VERSION 5.7 ;
  NOWIREEXTENSIONATPIN ON ;
  DIVIDERCHAR "/" ;
  BUSBITCHARS "[]" ;
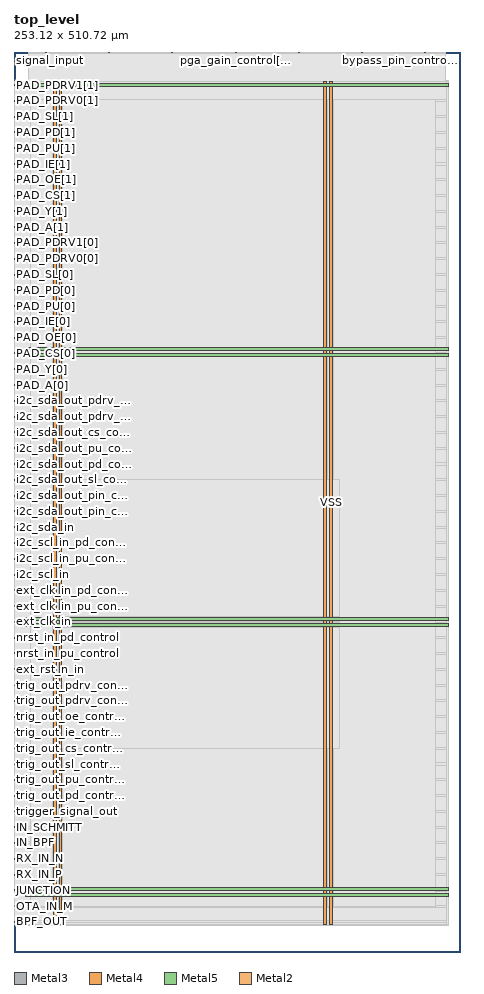
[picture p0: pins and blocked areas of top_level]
MACRO top_level
  CLASS BLOCK ;
  FOREIGN top_level ;
  ORIGIN 0.000 0.000 ;
  SIZE 253.120 BY 510.720 ;
  PIN BPF_OUT
    DIRECTION INPUT ;
    USE SIGNAL ;
    PORT
      LAYER Metal3 ;
        RECT 0.000 16.800 0.560 17.360 ;
    END
  END BPF_OUT
  PIN IN_BPF
    DIRECTION INPUT ;
    USE SIGNAL ;
    PORT
      LAYER Metal3 ;
        RECT 0.000 61.600 0.560 62.160 ;
    END
  END IN_BPF
  PIN IN_SCHMITT
    DIRECTION INPUT ;
    USE SIGNAL ;
    PORT
      LAYER Metal3 ;
        RECT 0.000 70.560 0.560 71.120 ;
    END
  END IN_SCHMITT
  PIN JUNCTION
    DIRECTION INPUT ;
    USE SIGNAL ;
    PORT
      LAYER Metal3 ;
        RECT 0.000 34.720 0.560 35.280 ;
    END
  END JUNCTION
  PIN OTA_IN_M
    DIRECTION INPUT ;
    USE SIGNAL ;
    PORT
      LAYER Metal3 ;
        RECT 0.000 25.760 0.560 26.320 ;
    END
  END OTA_IN_M
  PIN PAD_A[0]
    DIRECTION OUTPUT ;
    USE SIGNAL ;
    ANTENNADIFFAREA 0.897600 ;
    PORT
      LAYER Metal3 ;
        RECT 0.000 321.440 0.560 322.000 ;
    END
  END PAD_A[0]
  PIN PAD_A[1]
    DIRECTION OUTPUT ;
    USE SIGNAL ;
    ANTENNADIFFAREA 0.897600 ;
    PORT
      LAYER Metal3 ;
        RECT 0.000 411.040 0.560 411.600 ;
    END
  END PAD_A[1]
  PIN PAD_CS[0]
    DIRECTION OUTPUT ;
    USE SIGNAL ;
    ANTENNADIFFAREA 0.897600 ;
    PORT
      LAYER Metal3 ;
        RECT 0.000 339.360 0.560 339.920 ;
    END
  END PAD_CS[0]
  PIN PAD_CS[1]
    DIRECTION OUTPUT ;
    USE SIGNAL ;
    ANTENNADIFFAREA 0.897600 ;
    PORT
      LAYER Metal3 ;
        RECT 0.000 428.960 0.560 429.520 ;
    END
  END PAD_CS[1]
  PIN PAD_IE[0]
    DIRECTION OUTPUT ;
    USE SIGNAL ;
    ANTENNADIFFAREA 0.897600 ;
    PORT
      LAYER Metal3 ;
        RECT 0.000 357.280 0.560 357.840 ;
    END
  END PAD_IE[0]
  PIN PAD_IE[1]
    DIRECTION OUTPUT ;
    USE SIGNAL ;
    ANTENNADIFFAREA 0.897600 ;
    PORT
      LAYER Metal3 ;
        RECT 0.000 446.880 0.560 447.440 ;
    END
  END PAD_IE[1]
  PIN PAD_OE[0]
    DIRECTION OUTPUT ;
    USE SIGNAL ;
    ANTENNADIFFAREA 0.897600 ;
    PORT
      LAYER Metal3 ;
        RECT 0.000 348.320 0.560 348.880 ;
    END
  END PAD_OE[0]
  PIN PAD_OE[1]
    DIRECTION OUTPUT ;
    USE SIGNAL ;
    ANTENNADIFFAREA 0.897600 ;
    PORT
      LAYER Metal3 ;
        RECT 0.000 437.920 0.560 438.480 ;
    END
  END PAD_OE[1]
  PIN PAD_PDRV0[0]
    DIRECTION OUTPUT ;
    USE SIGNAL ;
    ANTENNADIFFAREA 0.536800 ;
    PORT
      LAYER Metal3 ;
        RECT 0.000 393.120 0.560 393.680 ;
    END
  END PAD_PDRV0[0]
  PIN PAD_PDRV0[1]
    DIRECTION OUTPUT ;
    USE SIGNAL ;
    ANTENNADIFFAREA 0.536800 ;
    PORT
      LAYER Metal3 ;
        RECT 0.000 482.720 0.560 483.280 ;
    END
  END PAD_PDRV0[1]
  PIN PAD_PDRV1[0]
    DIRECTION OUTPUT ;
    USE SIGNAL ;
    ANTENNADIFFAREA 0.536800 ;
    PORT
      LAYER Metal3 ;
        RECT 0.000 402.080 0.560 402.640 ;
    END
  END PAD_PDRV1[0]
  PIN PAD_PDRV1[1]
    DIRECTION OUTPUT ;
    USE SIGNAL ;
    ANTENNADIFFAREA 0.536800 ;
    PORT
      LAYER Metal3 ;
        RECT 0.000 491.680 0.560 492.240 ;
    END
  END PAD_PDRV1[1]
  PIN PAD_PD[0]
    DIRECTION OUTPUT ;
    USE SIGNAL ;
    ANTENNADIFFAREA 0.897600 ;
    PORT
      LAYER Metal3 ;
        RECT 0.000 375.200 0.560 375.760 ;
    END
  END PAD_PD[0]
  PIN PAD_PD[1]
    DIRECTION OUTPUT ;
    USE SIGNAL ;
    ANTENNADIFFAREA 0.897600 ;
    PORT
      LAYER Metal3 ;
        RECT 0.000 464.800 0.560 465.360 ;
    END
  END PAD_PD[1]
  PIN PAD_PU[0]
    DIRECTION OUTPUT ;
    USE SIGNAL ;
    ANTENNADIFFAREA 0.897600 ;
    PORT
      LAYER Metal3 ;
        RECT 0.000 366.240 0.560 366.800 ;
    END
  END PAD_PU[0]
  PIN PAD_PU[1]
    DIRECTION OUTPUT ;
    USE SIGNAL ;
    ANTENNADIFFAREA 0.897600 ;
    PORT
      LAYER Metal3 ;
        RECT 0.000 455.840 0.560 456.400 ;
    END
  END PAD_PU[1]
  PIN PAD_SL[0]
    DIRECTION OUTPUT ;
    USE SIGNAL ;
    ANTENNADIFFAREA 0.897600 ;
    PORT
      LAYER Metal3 ;
        RECT 0.000 384.160 0.560 384.720 ;
    END
  END PAD_SL[0]
  PIN PAD_SL[1]
    DIRECTION OUTPUT ;
    USE SIGNAL ;
    ANTENNADIFFAREA 0.897600 ;
    PORT
      LAYER Metal3 ;
        RECT 0.000 473.760 0.560 474.320 ;
    END
  END PAD_SL[1]
  PIN PAD_Y[0]
    DIRECTION INPUT ;
    USE SIGNAL ;
    ANTENNAGATEAREA 0.396000 ;
    PORT
      LAYER Metal3 ;
        RECT 0.000 330.400 0.560 330.960 ;
    END
  END PAD_Y[0]
  PIN PAD_Y[1]
    DIRECTION INPUT ;
    USE SIGNAL ;
    ANTENNAGATEAREA 0.396000 ;
    PORT
      LAYER Metal3 ;
        RECT 0.000 420.000 0.560 420.560 ;
    END
  END PAD_Y[1]
  PIN RX_IN_N
    DIRECTION INPUT ;
    USE SIGNAL ;
    PORT
      LAYER Metal3 ;
        RECT 0.000 52.640 0.560 53.200 ;
    END
  END RX_IN_N
  PIN RX_IN_P
    DIRECTION INPUT ;
    USE SIGNAL ;
    PORT
      LAYER Metal3 ;
        RECT 0.000 43.680 0.560 44.240 ;
    END
  END RX_IN_P
  PIN VDD
    DIRECTION INOUT ;
    USE POWER ;
    PORT
      LAYER Metal4 ;
        RECT 22.240 15.380 23.840 494.220 ;
    END
    PORT
      LAYER Metal4 ;
        RECT 175.840 15.380 177.440 494.220 ;
    END
    PORT
      LAYER Metal5 ;
        RECT 6.720 31.530 246.400 33.130 ;
    END
    PORT
      LAYER Metal5 ;
        RECT 6.720 184.710 246.400 186.310 ;
    END
    PORT
      LAYER Metal5 ;
        RECT 6.720 337.890 246.400 339.490 ;
    END
    PORT
      LAYER Metal5 ;
        RECT 6.720 491.070 246.400 492.670 ;
    END
  END VDD
  PIN VSS
    DIRECTION INOUT ;
    USE GROUND ;
    PORT
      LAYER Metal4 ;
        RECT 25.540 15.380 27.140 494.220 ;
    END
    PORT
      LAYER Metal4 ;
        RECT 179.140 15.380 180.740 494.220 ;
    END
    PORT
      LAYER Metal5 ;
        RECT 6.720 34.830 246.400 36.430 ;
    END
    PORT
      LAYER Metal5 ;
        RECT 6.720 188.010 246.400 189.610 ;
    END
    PORT
      LAYER Metal5 ;
        RECT 6.720 341.190 246.400 342.790 ;
    END
  END VSS
  PIN bypass_pin_control[0]
    DIRECTION OUTPUT ;
    USE SIGNAL ;
    ANTENNADIFFAREA 0.897600 ;
    PORT
      LAYER Metal2 ;
        RECT 232.960 510.160 233.520 510.720 ;
    END
  END bypass_pin_control[0]
  PIN bypass_pin_control[1]
    DIRECTION OUTPUT ;
    USE SIGNAL ;
    ANTENNADIFFAREA 0.897600 ;
    PORT
      LAYER Metal2 ;
        RECT 197.120 510.160 197.680 510.720 ;
    END
  END bypass_pin_control[1]
  PIN bypass_pin_control[2]
    DIRECTION OUTPUT ;
    USE SIGNAL ;
    ANTENNADIFFAREA 0.897600 ;
    PORT
      LAYER Metal2 ;
        RECT 161.280 510.160 161.840 510.720 ;
    END
  END bypass_pin_control[2]
  PIN ext_clk_in
    DIRECTION INPUT ;
    USE SIGNAL ;
    ANTENNAGATEAREA 4.738000 ;
    PORT
      LAYER Metal3 ;
        RECT 0.000 187.040 0.560 187.600 ;
    END
  END ext_clk_in
  PIN ext_clk_in_pd_control
    DIRECTION OUTPUT ;
    USE SIGNAL ;
    ANTENNADIFFAREA 0.360800 ;
    PORT
      LAYER Metal3 ;
        RECT 0.000 204.960 0.560 205.520 ;
    END
  END ext_clk_in_pd_control
  PIN ext_clk_in_pu_control
    DIRECTION OUTPUT ;
    USE SIGNAL ;
    ANTENNADIFFAREA 0.360800 ;
    PORT
      LAYER Metal3 ;
        RECT 0.000 196.000 0.560 196.560 ;
    END
  END ext_clk_in_pu_control
  PIN ext_rst_n_in
    DIRECTION INPUT ;
    USE SIGNAL ;
    ANTENNAGATEAREA 0.396000 ;
    PORT
      LAYER Metal3 ;
        RECT 0.000 160.160 0.560 160.720 ;
    END
  END ext_rst_n_in
  PIN i2c_scl_in
    DIRECTION INPUT ;
    USE SIGNAL ;
    ANTENNAGATEAREA 0.396000 ;
    PORT
      LAYER Metal3 ;
        RECT 0.000 213.920 0.560 214.480 ;
    END
  END i2c_scl_in
  PIN i2c_scl_in_pd_control
    DIRECTION OUTPUT ;
    USE SIGNAL ;
    ANTENNADIFFAREA 0.360800 ;
    PORT
      LAYER Metal3 ;
        RECT 0.000 231.840 0.560 232.400 ;
    END
  END i2c_scl_in_pd_control
  PIN i2c_scl_in_pu_control
    DIRECTION OUTPUT ;
    USE SIGNAL ;
    ANTENNADIFFAREA 0.536800 ;
    PORT
      LAYER Metal3 ;
        RECT 0.000 222.880 0.560 223.440 ;
    END
  END i2c_scl_in_pu_control
  PIN i2c_sda_in
    DIRECTION INPUT ;
    USE SIGNAL ;
    ANTENNAGATEAREA 0.396000 ;
    PORT
      LAYER Metal3 ;
        RECT 0.000 240.800 0.560 241.360 ;
    END
  END i2c_sda_in
  PIN i2c_sda_out_cs_control
    DIRECTION OUTPUT ;
    USE SIGNAL ;
    ANTENNADIFFAREA 0.536800 ;
    PORT
      LAYER Metal3 ;
        RECT 0.000 294.560 0.560 295.120 ;
    END
  END i2c_sda_out_cs_control
  PIN i2c_sda_out_pd_control
    DIRECTION OUTPUT ;
    USE SIGNAL ;
    ANTENNADIFFAREA 0.360800 ;
    PORT
      LAYER Metal3 ;
        RECT 0.000 276.640 0.560 277.200 ;
    END
  END i2c_sda_out_pd_control
  PIN i2c_sda_out_pdrv_control[0]
    DIRECTION OUTPUT ;
    USE SIGNAL ;
    ANTENNADIFFAREA 0.536800 ;
    PORT
      LAYER Metal3 ;
        RECT 0.000 312.480 0.560 313.040 ;
    END
  END i2c_sda_out_pdrv_control[0]
  PIN i2c_sda_out_pdrv_control[1]
    DIRECTION OUTPUT ;
    USE SIGNAL ;
    ANTENNADIFFAREA 0.536800 ;
    PORT
      LAYER Metal3 ;
        RECT 0.000 303.520 0.560 304.080 ;
    END
  END i2c_sda_out_pdrv_control[1]
  PIN i2c_sda_out_pin_ctrl
    DIRECTION OUTPUT ;
    USE SIGNAL ;
    ANTENNADIFFAREA 0.897600 ;
    PORT
      LAYER Metal3 ;
        RECT 0.000 249.760 0.560 250.320 ;
    END
  END i2c_sda_out_pin_ctrl
  PIN i2c_sda_out_pin_ctrl_n
    DIRECTION OUTPUT ;
    USE SIGNAL ;
    ANTENNADIFFAREA 0.897600 ;
    PORT
      LAYER Metal3 ;
        RECT 0.000 258.720 0.560 259.280 ;
    END
  END i2c_sda_out_pin_ctrl_n
  PIN i2c_sda_out_pu_control
    DIRECTION OUTPUT ;
    USE SIGNAL ;
    ANTENNADIFFAREA 0.536800 ;
    PORT
      LAYER Metal3 ;
        RECT 0.000 285.600 0.560 286.160 ;
    END
  END i2c_sda_out_pu_control
  PIN i2c_sda_out_sl_control
    DIRECTION OUTPUT ;
    USE SIGNAL ;
    ANTENNADIFFAREA 0.360800 ;
    PORT
      LAYER Metal3 ;
        RECT 0.000 267.680 0.560 268.240 ;
    END
  END i2c_sda_out_sl_control
  PIN nrst_in_pd_control
    DIRECTION OUTPUT ;
    USE SIGNAL ;
    ANTENNADIFFAREA 0.360800 ;
    PORT
      LAYER Metal3 ;
        RECT 0.000 178.080 0.560 178.640 ;
    END
  END nrst_in_pd_control
  PIN nrst_in_pu_control
    DIRECTION OUTPUT ;
    USE SIGNAL ;
    ANTENNADIFFAREA 0.536800 ;
    PORT
      LAYER Metal3 ;
        RECT 0.000 169.120 0.560 169.680 ;
    END
  END nrst_in_pu_control
  PIN pga_gain_control[0]
    DIRECTION OUTPUT ;
    USE SIGNAL ;
    ANTENNADIFFAREA 0.897600 ;
    PORT
      LAYER Metal2 ;
        RECT 125.440 510.160 126.000 510.720 ;
    END
  END pga_gain_control[0]
  PIN pga_gain_control[1]
    DIRECTION OUTPUT ;
    USE SIGNAL ;
    ANTENNADIFFAREA 0.897600 ;
    PORT
      LAYER Metal2 ;
        RECT 89.600 510.160 90.160 510.720 ;
    END
  END pga_gain_control[1]
  PIN pga_gain_control[2]
    DIRECTION OUTPUT ;
    USE SIGNAL ;
    ANTENNADIFFAREA 0.897600 ;
    PORT
      LAYER Metal2 ;
        RECT 53.760 510.160 54.320 510.720 ;
    END
  END pga_gain_control[2]
  PIN signal_input
    DIRECTION INPUT ;
    USE SIGNAL ;
    ANTENNAGATEAREA 9.476000 ;
    PORT
      LAYER Metal2 ;
        RECT 17.920 510.160 18.480 510.720 ;
    END
  END signal_input
  PIN trig_out_cs_control
    DIRECTION OUTPUT ;
    USE SIGNAL ;
    ANTENNADIFFAREA 0.360800 ;
    PORT
      LAYER Metal3 ;
        RECT 0.000 115.360 0.560 115.920 ;
    END
  END trig_out_cs_control
  PIN trig_out_ie_control
    DIRECTION OUTPUT ;
    USE SIGNAL ;
    ANTENNADIFFAREA 0.360800 ;
    PORT
      LAYER Metal3 ;
        RECT 0.000 124.320 0.560 124.880 ;
    END
  END trig_out_ie_control
  PIN trig_out_oe_control
    DIRECTION OUTPUT ;
    USE SIGNAL ;
    ANTENNADIFFAREA 0.536800 ;
    PORT
      LAYER Metal3 ;
        RECT 0.000 133.280 0.560 133.840 ;
    END
  END trig_out_oe_control
  PIN trig_out_pd_control
    DIRECTION OUTPUT ;
    USE SIGNAL ;
    ANTENNADIFFAREA 0.536800 ;
    PORT
      LAYER Metal3 ;
        RECT 0.000 88.480 0.560 89.040 ;
    END
  END trig_out_pd_control
  PIN trig_out_pdrv_control[0]
    DIRECTION OUTPUT ;
    USE SIGNAL ;
    ANTENNADIFFAREA 0.536800 ;
    PORT
      LAYER Metal3 ;
        RECT 0.000 151.200 0.560 151.760 ;
    END
  END trig_out_pdrv_control[0]
  PIN trig_out_pdrv_control[1]
    DIRECTION OUTPUT ;
    USE SIGNAL ;
    ANTENNADIFFAREA 0.536800 ;
    PORT
      LAYER Metal3 ;
        RECT 0.000 142.240 0.560 142.800 ;
    END
  END trig_out_pdrv_control[1]
  PIN trig_out_pu_control
    DIRECTION OUTPUT ;
    USE SIGNAL ;
    ANTENNADIFFAREA 0.360800 ;
    PORT
      LAYER Metal3 ;
        RECT 0.000 97.440 0.560 98.000 ;
    END
  END trig_out_pu_control
  PIN trig_out_sl_control
    DIRECTION OUTPUT ;
    USE SIGNAL ;
    ANTENNADIFFAREA 0.360800 ;
    PORT
      LAYER Metal3 ;
        RECT 0.000 106.400 0.560 106.960 ;
    END
  END trig_out_sl_control
  PIN trigger_signal_out
    DIRECTION OUTPUT ;
    USE SIGNAL ;
    ANTENNADIFFAREA 0.897600 ;
    PORT
      LAYER Metal3 ;
        RECT 0.000 79.520 0.560 80.080 ;
    END
  END trigger_signal_out
  OBS
      LAYER Nwell ;
        RECT 6.290 15.250 246.830 494.350 ;
      LAYER Metal1 ;
        RECT 6.720 15.380 246.400 494.220 ;
      LAYER Metal2 ;
        RECT 7.980 509.860 17.620 510.160 ;
        RECT 18.780 509.860 53.460 510.160 ;
        RECT 54.620 509.860 89.300 510.160 ;
        RECT 90.460 509.860 125.140 510.160 ;
        RECT 126.300 509.860 160.980 510.160 ;
        RECT 162.140 509.860 196.820 510.160 ;
        RECT 197.980 509.860 232.660 510.160 ;
        RECT 233.820 509.860 245.140 510.160 ;
        RECT 7.980 15.490 245.140 509.860 ;
      LAYER Metal3 ;
        RECT 0.560 492.540 245.190 494.060 ;
        RECT 0.860 491.380 245.190 492.540 ;
        RECT 0.560 483.580 245.190 491.380 ;
        RECT 0.860 482.420 245.190 483.580 ;
        RECT 0.560 474.620 245.190 482.420 ;
        RECT 0.860 473.460 245.190 474.620 ;
        RECT 0.560 465.660 245.190 473.460 ;
        RECT 0.860 464.500 245.190 465.660 ;
        RECT 0.560 456.700 245.190 464.500 ;
        RECT 0.860 455.540 245.190 456.700 ;
        RECT 0.560 447.740 245.190 455.540 ;
        RECT 0.860 446.580 245.190 447.740 ;
        RECT 0.560 438.780 245.190 446.580 ;
        RECT 0.860 437.620 245.190 438.780 ;
        RECT 0.560 429.820 245.190 437.620 ;
        RECT 0.860 428.660 245.190 429.820 ;
        RECT 0.560 420.860 245.190 428.660 ;
        RECT 0.860 419.700 245.190 420.860 ;
        RECT 0.560 411.900 245.190 419.700 ;
        RECT 0.860 410.740 245.190 411.900 ;
        RECT 0.560 402.940 245.190 410.740 ;
        RECT 0.860 401.780 245.190 402.940 ;
        RECT 0.560 393.980 245.190 401.780 ;
        RECT 0.860 392.820 245.190 393.980 ;
        RECT 0.560 385.020 245.190 392.820 ;
        RECT 0.860 383.860 245.190 385.020 ;
        RECT 0.560 376.060 245.190 383.860 ;
        RECT 0.860 374.900 245.190 376.060 ;
        RECT 0.560 367.100 245.190 374.900 ;
        RECT 0.860 365.940 245.190 367.100 ;
        RECT 0.560 358.140 245.190 365.940 ;
        RECT 0.860 356.980 245.190 358.140 ;
        RECT 0.560 349.180 245.190 356.980 ;
        RECT 0.860 348.020 245.190 349.180 ;
        RECT 0.560 340.220 245.190 348.020 ;
        RECT 0.860 339.060 245.190 340.220 ;
        RECT 0.560 331.260 245.190 339.060 ;
        RECT 0.860 330.100 245.190 331.260 ;
        RECT 0.560 322.300 245.190 330.100 ;
        RECT 0.860 321.140 245.190 322.300 ;
        RECT 0.560 313.340 245.190 321.140 ;
        RECT 0.860 312.180 245.190 313.340 ;
        RECT 0.560 304.380 245.190 312.180 ;
        RECT 0.860 303.220 245.190 304.380 ;
        RECT 0.560 295.420 245.190 303.220 ;
        RECT 0.860 294.260 245.190 295.420 ;
        RECT 0.560 286.460 245.190 294.260 ;
        RECT 0.860 285.300 245.190 286.460 ;
        RECT 0.560 277.500 245.190 285.300 ;
        RECT 0.860 276.340 245.190 277.500 ;
        RECT 0.560 268.540 245.190 276.340 ;
        RECT 0.860 267.380 245.190 268.540 ;
        RECT 0.560 259.580 245.190 267.380 ;
        RECT 0.860 258.420 245.190 259.580 ;
        RECT 0.560 250.620 245.190 258.420 ;
        RECT 0.860 249.460 245.190 250.620 ;
        RECT 0.560 241.660 245.190 249.460 ;
        RECT 0.860 240.500 245.190 241.660 ;
        RECT 0.560 232.700 245.190 240.500 ;
        RECT 0.860 231.540 245.190 232.700 ;
        RECT 0.560 223.740 245.190 231.540 ;
        RECT 0.860 222.580 245.190 223.740 ;
        RECT 0.560 214.780 245.190 222.580 ;
        RECT 0.860 213.620 245.190 214.780 ;
        RECT 0.560 205.820 245.190 213.620 ;
        RECT 0.860 204.660 245.190 205.820 ;
        RECT 0.560 196.860 245.190 204.660 ;
        RECT 0.860 195.700 245.190 196.860 ;
        RECT 0.560 187.900 245.190 195.700 ;
        RECT 0.860 186.740 245.190 187.900 ;
        RECT 0.560 178.940 245.190 186.740 ;
        RECT 0.860 177.780 245.190 178.940 ;
        RECT 0.560 169.980 245.190 177.780 ;
        RECT 0.860 168.820 245.190 169.980 ;
        RECT 0.560 161.020 245.190 168.820 ;
        RECT 0.860 159.860 245.190 161.020 ;
        RECT 0.560 152.060 245.190 159.860 ;
        RECT 0.860 150.900 245.190 152.060 ;
        RECT 0.560 143.100 245.190 150.900 ;
        RECT 0.860 141.940 245.190 143.100 ;
        RECT 0.560 134.140 245.190 141.940 ;
        RECT 0.860 132.980 245.190 134.140 ;
        RECT 0.560 125.180 245.190 132.980 ;
        RECT 0.860 124.020 245.190 125.180 ;
        RECT 0.560 116.220 245.190 124.020 ;
        RECT 0.860 115.060 245.190 116.220 ;
        RECT 0.560 107.260 245.190 115.060 ;
        RECT 0.860 106.100 245.190 107.260 ;
        RECT 0.560 98.300 245.190 106.100 ;
        RECT 0.860 97.140 245.190 98.300 ;
        RECT 0.560 89.340 245.190 97.140 ;
        RECT 0.860 88.180 245.190 89.340 ;
        RECT 0.560 80.380 245.190 88.180 ;
        RECT 0.860 79.220 245.190 80.380 ;
        RECT 0.560 71.420 245.190 79.220 ;
        RECT 0.860 70.260 245.190 71.420 ;
        RECT 0.560 62.460 245.190 70.260 ;
        RECT 0.860 61.300 245.190 62.460 ;
        RECT 0.560 53.500 245.190 61.300 ;
        RECT 0.860 52.340 245.190 53.500 ;
        RECT 0.560 44.540 245.190 52.340 ;
        RECT 0.860 43.380 245.190 44.540 ;
        RECT 0.560 35.580 245.190 43.380 ;
        RECT 0.860 34.420 245.190 35.580 ;
        RECT 0.560 26.620 245.190 34.420 ;
        RECT 0.860 25.460 245.190 26.620 ;
        RECT 0.560 17.660 245.190 25.460 ;
        RECT 0.860 16.500 245.190 17.660 ;
        RECT 0.560 15.540 245.190 16.500 ;
      LAYER Metal4 ;
        RECT 9.100 25.850 21.940 483.750 ;
        RECT 24.140 25.850 25.240 483.750 ;
        RECT 27.440 25.850 175.540 483.750 ;
        RECT 177.740 25.850 178.840 483.750 ;
        RECT 181.040 25.850 238.980 483.750 ;
      LAYER Metal5 ;
        RECT 26.940 190.210 184.740 267.970 ;
        RECT 26.940 186.910 184.740 187.410 ;
        RECT 26.940 115.430 184.740 184.110 ;
  END
END top_level
END LIBRARY

